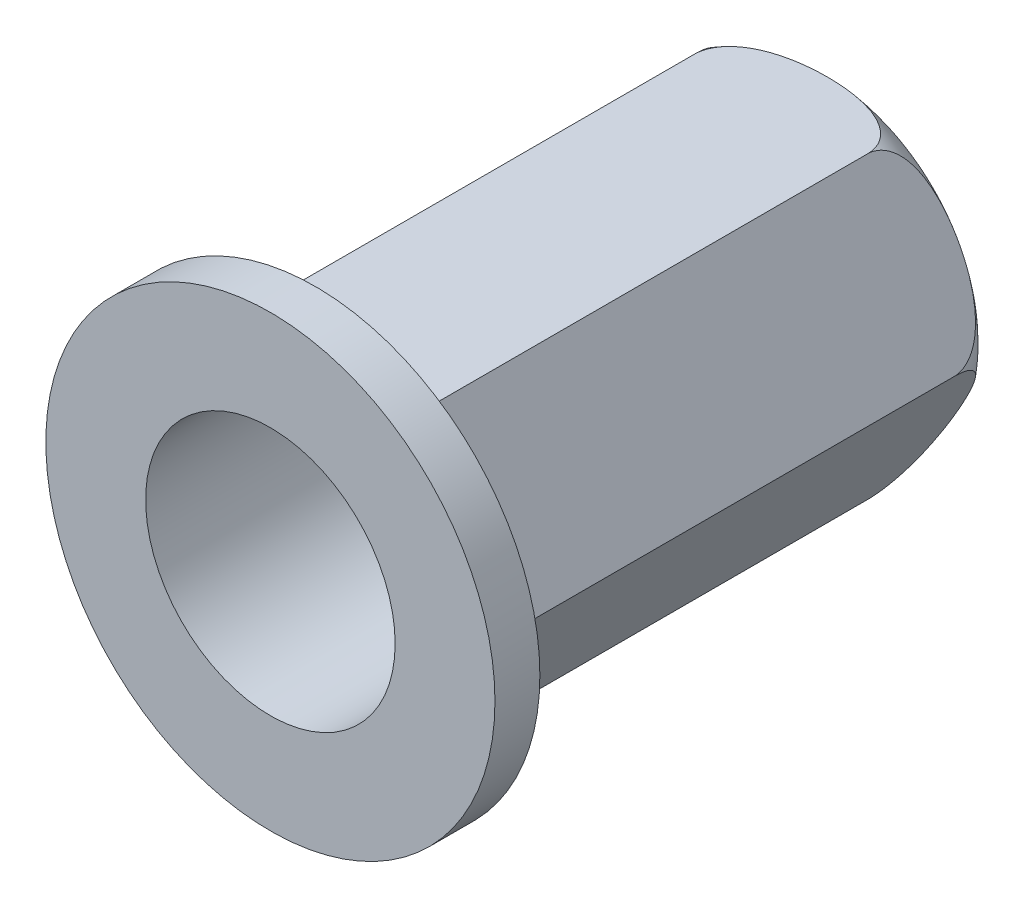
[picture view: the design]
ISO-10303-21;
HEADER;
FILE_DESCRIPTION(('STEP AP214'),'2;1');
FILE_NAME('part.step','',(''),(''),'','','');
FILE_SCHEMA(('AUTOMOTIVE_DESIGN { 1 0 10303 214 1 1 1 1 }'));
ENDSEC;
DATA;
#1=APPLICATION_CONTEXT('core data for automotive mechanical design processes');
#2=APPLICATION_PROTOCOL_DEFINITION('international standard','automotive_design',2000,#1);
#3=PRODUCT_CONTEXT('',#1,'mechanical');
#4=PRODUCT('Part','Part','',(#3));
#5=PRODUCT_RELATED_PRODUCT_CATEGORY('part','',(#4));
#6=PRODUCT_DEFINITION_FORMATION('','',#4);
#7=PRODUCT_DEFINITION_CONTEXT('part definition',#1,'design');
#8=PRODUCT_DEFINITION('design','',#6,#7);
#9=PRODUCT_DEFINITION_SHAPE('','',#8);
#10=(LENGTH_UNIT() NAMED_UNIT(*) SI_UNIT(.MILLI.,.METRE.));
#11=(NAMED_UNIT(*) PLANE_ANGLE_UNIT() SI_UNIT($,.RADIAN.));
#12=(NAMED_UNIT(*) SI_UNIT($,.STERADIAN.) SOLID_ANGLE_UNIT());
#13=UNCERTAINTY_MEASURE_WITH_UNIT(LENGTH_MEASURE(1.E-05),#10,'distance_accuracy_value','');
#14=(GEOMETRIC_REPRESENTATION_CONTEXT(3) GLOBAL_UNCERTAINTY_ASSIGNED_CONTEXT((#13)) GLOBAL_UNIT_ASSIGNED_CONTEXT((#10,
#11,#12)) REPRESENTATION_CONTEXT('',''));
#15=CARTESIAN_POINT('',(0.,0.,0.));
#16=DIRECTION('',(0.,0.,1.));
#17=DIRECTION('',(1.,0.,0.));
#18=AXIS2_PLACEMENT_3D('',#15,#16,#17);
#19=CARTESIAN_POINT('',(-3.46410161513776,6.,-22.8000000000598));
#20=DIRECTION('',(0.,-1.,0.));
#21=DIRECTION('',(1.,0.,0.));
#22=AXIS2_PLACEMENT_3D('',#19,#20,#21);
#23=PLANE('',#22);
#24=DIRECTION('',(0.,0.,1.));
#25=VECTOR('',#24,1.);
#26=CARTESIAN_POINT('',(-3.46410161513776,6.,-22.8000000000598));
#27=LINE('',#26,#25);
#28=CARTESIAN_POINT('',(-3.46410161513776,6.,-20.4666666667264));
#29=VERTEX_POINT('',#28);
#30=CARTESIAN_POINT('',(-3.46410161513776,6.,-2.70000000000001));
#31=VERTEX_POINT('',#30);
#32=EDGE_CURVE('E317',#29,#31,#27,.T.);
#33=ORIENTED_EDGE('',*,*,#32,.T.);
#34=DIRECTION('',(1.,0.,0.));
#35=VECTOR('',#34,1.);
#36=CARTESIAN_POINT('',(3.46410161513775,6.,-2.7));
#37=LINE('',#36,#35);
#38=CARTESIAN_POINT('',(3.46410161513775,6.,-2.70000000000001));
#39=VERTEX_POINT('',#38);
#40=EDGE_CURVE('E58',#31,#39,#37,.T.);
#41=ORIENTED_EDGE('',*,*,#40,.T.);
#42=DIRECTION('',(0.,0.,1.));
#43=VECTOR('',#42,1.);
#44=CARTESIAN_POINT('',(3.46410161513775,6.,-22.8000000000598));
#45=LINE('',#44,#43);
#46=CARTESIAN_POINT('',(3.46410161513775,6.00000000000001,-20.4666666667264));
#47=VERTEX_POINT('',#46);
#48=EDGE_CURVE('E126',#47,#39,#45,.T.);
#49=ORIENTED_EDGE('',*,*,#48,.F.);
#50=CARTESIAN_POINT('',(0.,6.,-22.3294747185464));
#51=CARTESIAN_POINT('',(0.154184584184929,6.,-22.3294717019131));
#52=CARTESIAN_POINT('',(0.308365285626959,6.,-22.3250239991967));
#53=CARTESIAN_POINT('',(0.616274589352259,6.,-22.3068259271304));
#54=CARTESIAN_POINT('',(0.770002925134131,6.,-22.2930708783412));
#55=CARTESIAN_POINT('',(1.07581899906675,6.,-22.2551025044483));
#56=CARTESIAN_POINT('',(1.22790980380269,6.,-22.2309145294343));
#57=CARTESIAN_POINT('',(1.52950724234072,6.,-22.1700841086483));
#58=CARTESIAN_POINT('',(1.67901642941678,6.,-22.1334548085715));
#59=CARTESIAN_POINT('',(1.94993108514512,6.,-22.0519178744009));
#60=CARTESIAN_POINT('',(2.07200596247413,6.,-22.0092722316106));
#61=CARTESIAN_POINT('',(2.31103064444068,6.,-21.9108273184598));
#62=CARTESIAN_POINT('',(2.42797468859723,6.,-21.8550136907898));
#63=CARTESIAN_POINT('',(2.65466542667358,6.,-21.7268580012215));
#64=CARTESIAN_POINT('',(2.76429762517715,6.,-21.6543087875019));
#65=CARTESIAN_POINT('',(2.96863454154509,6.,-21.4905393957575));
#66=CARTESIAN_POINT('',(3.06339501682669,6.,-21.3993920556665));
#67=CARTESIAN_POINT('',(3.19489580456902,6.,-21.2393492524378));
#68=CARTESIAN_POINT('',(3.23941987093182,6.,-21.1768508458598));
#69=CARTESIAN_POINT('',(3.31809199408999,6.,-21.0455705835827));
#70=CARTESIAN_POINT('',(3.35224628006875,6.,-20.9767925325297));
#71=CARTESIAN_POINT('',(3.40811056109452,6.,-20.8335865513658));
#72=CARTESIAN_POINT('',(3.42971034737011,6.,-20.7591148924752));
#73=CARTESIAN_POINT('',(3.45810849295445,6.,-20.6073950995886));
#74=CARTESIAN_POINT('',(3.46491843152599,6.,-20.5301491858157));
#75=CARTESIAN_POINT('',(3.46323187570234,6.,-20.3850698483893));
#76=CARTESIAN_POINT('',(3.45646076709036,6.,-20.317210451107));
#77=CARTESIAN_POINT('',(3.43148910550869,6.,-20.1836465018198));
#78=CARTESIAN_POINT('',(3.41328766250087,6.,-20.1179421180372));
#79=CARTESIAN_POINT('',(3.36687234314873,6.,-19.9908236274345));
#80=CARTESIAN_POINT('',(3.33874008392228,6.,-19.9293792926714));
#81=CARTESIAN_POINT('',(3.27399756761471,6.,-19.8111755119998));
#82=CARTESIAN_POINT('',(3.23738389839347,6.,-19.754417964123));
#83=CARTESIAN_POINT('',(3.13607560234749,6.,-19.6174288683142));
#84=CARTESIAN_POINT('',(3.06675759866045,6.,-19.5406125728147));
#85=CARTESIAN_POINT('',(2.91680568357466,6.,-19.3989627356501));
#86=CARTESIAN_POINT('',(2.83614367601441,6.,-19.3341599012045));
#87=CARTESIAN_POINT('',(2.61923773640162,6.,-19.1819547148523));
#88=CARTESIAN_POINT('',(2.47740993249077,6.,-19.1025706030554));
#89=CARTESIAN_POINT('',(2.18369947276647,6.,-18.9658033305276));
#90=CARTESIAN_POINT('',(2.03179656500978,6.,-18.9084661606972));
#91=CARTESIAN_POINT('',(1.73122572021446,6.,-18.813975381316));
#92=CARTESIAN_POINT('',(1.58284593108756,6.,-18.7758784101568));
#93=CARTESIAN_POINT('',(1.28333812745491,6.,-18.7122986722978));
#94=CARTESIAN_POINT('',(1.13220756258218,6.,-18.6868283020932));
#95=CARTESIAN_POINT('',(0.827947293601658,6.,-18.6463598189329));
#96=CARTESIAN_POINT('',(0.674811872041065,6.,-18.6314059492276));
#97=CARTESIAN_POINT('',(0.367996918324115,6.,-18.6108596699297));
#98=CARTESIAN_POINT('',(0.214317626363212,6.,-18.6052635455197));
#99=CARTESIAN_POINT('',(-0.112922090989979,6.,-18.6027641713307));
#100=CARTESIAN_POINT('',(-0.286492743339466,6.,-18.6070739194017));
#101=CARTESIAN_POINT('',(-0.633091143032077,6.,-18.627444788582));
#102=CARTESIAN_POINT('',(-0.806118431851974,6.,-18.6435140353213));
#103=CARTESIAN_POINT('',(-1.1498441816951,6.,-18.6891173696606));
#104=CARTESIAN_POINT('',(-1.32054853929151,6.,-18.7186057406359));
#105=CARTESIAN_POINT('',(-1.6581955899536,6.,-18.794096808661));
#106=CARTESIAN_POINT('',(-1.82514375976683,6.,-18.8400735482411));
#107=CARTESIAN_POINT('',(-2.07000778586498,6.,-18.9247765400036));
#108=CARTESIAN_POINT('',(-2.15064347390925,6.,-18.9556044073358));
#109=CARTESIAN_POINT('',(-2.30936935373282,6.,-19.0232052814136));
#110=CARTESIAN_POINT('',(-2.38745867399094,6.,-19.059980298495));
#111=CARTESIAN_POINT('',(-2.61579578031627,6.,-19.1800327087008));
#112=CARTESIAN_POINT('',(-2.76125765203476,6.,-19.2734038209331));
#113=CARTESIAN_POINT('',(-2.95841093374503,6.,-19.4366877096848));
#114=CARTESIAN_POINT('',(-3.02022108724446,6.,-19.4944504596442));
#115=CARTESIAN_POINT('',(-3.13514885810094,6.,-19.6182493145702));
#116=CARTESIAN_POINT('',(-3.18826346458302,6.,-19.6842882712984));
#117=CARTESIAN_POINT('',(-3.28337913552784,6.,-19.8251182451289));
#118=CARTESIAN_POINT('',(-3.32525323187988,6.,-19.8999965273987));
#119=CARTESIAN_POINT('',(-3.39377396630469,6.,-20.0564392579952));
#120=CARTESIAN_POINT('',(-3.42044481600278,6.,-20.1379928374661));
#121=CARTESIAN_POINT('',(-3.45387652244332,6.,-20.295254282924));
#122=CARTESIAN_POINT('',(-3.46258425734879,6.,-20.3705464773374));
#123=CARTESIAN_POINT('',(-3.46525164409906,6.,-20.5213846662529));
#124=CARTESIAN_POINT('',(-3.45921737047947,6.,-20.5969305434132));
#125=CARTESIAN_POINT('',(-3.43461422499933,6.,-20.7362646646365));
#126=CARTESIAN_POINT('',(-3.41768541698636,6.,-20.8003527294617));
#127=CARTESIAN_POINT('',(-3.37407256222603,6.,-20.9250874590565));
#128=CARTESIAN_POINT('',(-3.34738616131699,6.,-20.9857332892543));
#129=CARTESIAN_POINT('',(-3.27528134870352,6.,-21.1222767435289));
#130=CARTESIAN_POINT('',(-3.22658138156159,6.,-21.196439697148));
#131=CARTESIAN_POINT('',(-3.11781351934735,6.,-21.3358708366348));
#132=CARTESIAN_POINT('',(-3.05772509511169,6.,-21.401122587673));
#133=CARTESIAN_POINT('',(-2.90009049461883,6.,-21.5503465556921));
#134=CARTESIAN_POINT('',(-2.79791245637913,6.,-21.629395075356));
#135=CARTESIAN_POINT('',(-2.58266696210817,6.,-21.7708478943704));
#136=CARTESIAN_POINT('',(-2.46957433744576,6.,-21.8332124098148));
#137=CARTESIAN_POINT('',(-2.25226314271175,6.,-21.9364464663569));
#138=CARTESIAN_POINT('',(-2.14885789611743,6.,-21.9790700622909));
#139=CARTESIAN_POINT('',(-1.93871953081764,6.,-22.0552719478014));
#140=CARTESIAN_POINT('',(-1.83198377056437,6.,-22.0888428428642));
#141=CARTESIAN_POINT('',(-1.6163074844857,6.,-22.148268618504));
#142=CARTESIAN_POINT('',(-1.50736488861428,6.,-22.1741158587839));
#143=CARTESIAN_POINT('',(-1.28816765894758,6.,-22.2191255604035));
#144=CARTESIAN_POINT('',(-1.1779134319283,6.,-22.2382900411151));
#145=CARTESIAN_POINT('',(-0.890703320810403,6.,-22.2804820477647));
#146=CARTESIAN_POINT('',(-0.713086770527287,6.,-22.2990251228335));
#147=CARTESIAN_POINT('',(-0.356978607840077,6.,-22.323525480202));
#148=CARTESIAN_POINT('',(-0.17848670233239,6.,-22.3294782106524));
#149=CARTESIAN_POINT('',(0.,6.,-22.3294747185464));
#150=B_SPLINE_CURVE_WITH_KNOTS('',3,(#50,#51,#52,#53,#54,#55,#56,#57,#58,#59,#60,#61,#62,#63,
#64,#65,#66,#67,#68,#69,#70,#71,#72,#73,#74,#75,#76,#77,#78,#79,#80,#81,#82,#83,#84,#85,#86,#87,
#88,#89,#90,#91,#92,#93,#94,#95,#96,#97,#98,#99,#100,#101,#102,#103,#104,#105,#106,#107,#108,
#109,#110,#111,#112,#113,#114,#115,#116,#117,#118,#119,#120,#121,#122,#123,#124,#125,#126,#127,
#128,#129,#130,#131,#132,#133,#134,#135,#136,#137,#138,#139,#140,#141,#142,#143,#144,#145,#146,
#147,#148,#149),.UNSPECIFIED.,.T.,.F.,(4,2,2,2,2,2,2,2,2,2,2,2,2,2,2,2,2,2,2,2,2,2,2,2,2,2,2,2,
2,2,2,2,2,2,2,2,2,2,2,2,2,2,2,2,2,2,2,2,2,4),(0.,0.462479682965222,0.925192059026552,
1.38678640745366,1.84789453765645,2.23523118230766,2.62299211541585,3.01583805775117,
3.40717400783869,3.63659218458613,3.86587227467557,4.09713581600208,4.32821823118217,
4.53179583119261,4.73538928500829,4.93734702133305,5.13938614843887,5.44802668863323,
5.75744557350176,6.24229747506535,6.72815538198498,7.18705566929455,7.64640560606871,
8.10767666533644,8.56876456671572,9.08926420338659,9.61012383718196,10.1292221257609,
10.6475067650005,10.9062553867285,11.1650916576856,11.6791912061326,11.9323360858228,
12.1855684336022,12.4415511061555,12.6971249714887,12.9231229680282,13.1490278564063,
13.3470334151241,13.5450867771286,13.8097838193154,14.074962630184,14.4603581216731,
14.8466645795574,15.1817185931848,15.517045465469,15.8527029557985,16.1882589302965,
16.7234398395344,17.2588142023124),.UNSPECIFIED.);
#151=EDGE_CURVE('E114',#29,#47,#150,.T.);
#152=ORIENTED_EDGE('',*,*,#151,.F.);
#153=EDGE_LOOP('',(#33,#41,#49,#152));
#154=FACE_BOUND('',#153,.T.);
#155=ADVANCED_FACE('F35',(#154),#23,.F.);
#156=CARTESIAN_POINT('',(3.46410161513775,6.,-22.8000000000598));
#157=DIRECTION('',(-0.866025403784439,-0.5,0.));
#158=DIRECTION('',(0.5,-0.866025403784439,0.));
#159=AXIS2_PLACEMENT_3D('',#156,#157,#158);
#160=PLANE('',#159);
#161=ORIENTED_EDGE('',*,*,#48,.T.);
#162=DIRECTION('',(0.5,-0.866025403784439,0.));
#163=VECTOR('',#162,1.);
#164=CARTESIAN_POINT('',(6.92820323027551,0.,-2.7));
#165=LINE('',#164,#163);
#166=CARTESIAN_POINT('',(6.92820323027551,0.,-2.70000000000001));
#167=VERTEX_POINT('',#166);
#168=EDGE_CURVE('E50',#39,#167,#165,.T.);
#169=ORIENTED_EDGE('',*,*,#168,.T.);
#170=DIRECTION('',(0.,0.,1.));
#171=VECTOR('',#170,1.);
#172=CARTESIAN_POINT('',(6.92820323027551,0.,-22.8000000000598));
#173=LINE('',#172,#171);
#174=CARTESIAN_POINT('',(6.92820323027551,0.,-20.4666666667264));
#175=VERTEX_POINT('',#174);
#176=EDGE_CURVE('E119',#175,#167,#173,.T.);
#177=ORIENTED_EDGE('',*,*,#176,.F.);
#178=CARTESIAN_POINT('',(3.46410162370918,5.99999998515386,-20.4664666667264));
#179=CARTESIAN_POINT('',(3.46409613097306,6.00000949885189,-20.5007988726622));
#180=CARTESIAN_POINT('',(3.46485408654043,5.99869668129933,-20.5351131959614));
#181=CARTESIAN_POINT('',(3.46786667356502,5.99347872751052,-20.6034580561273));
#182=CARTESIAN_POINT('',(3.47012041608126,5.9895751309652,-20.6374887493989));
#183=CARTESIAN_POINT('',(3.47903492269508,5.97413475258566,-20.7383191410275));
#184=CARTESIAN_POINT('',(3.48784998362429,5.95886661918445,-20.8043983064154));
#185=CARTESIAN_POINT('',(3.51062418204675,5.91942055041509,-20.9326667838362));
#186=CARTESIAN_POINT('',(3.52457273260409,5.89526095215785,-20.9948637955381));
#187=CARTESIAN_POINT('',(3.55684476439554,5.83936415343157,-21.1146179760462));
#188=CARTESIAN_POINT('',(3.57517617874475,5.80761321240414,-21.1721664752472));
#189=CARTESIAN_POINT('',(3.62554504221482,5.72037178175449,-21.3097398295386));
#190=CARTESIAN_POINT('',(3.65983314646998,5.66098304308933,-21.3864692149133));
#191=CARTESIAN_POINT('',(3.73406030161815,5.5324178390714,-21.5280409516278));
#192=CARTESIAN_POINT('',(3.77401200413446,5.46321946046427,-21.5928559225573));
#193=CARTESIAN_POINT('',(3.88136050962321,5.27728639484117,-21.7449917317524));
#194=CARTESIAN_POINT('',(3.95153570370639,5.1557393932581,-21.8244109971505));
#195=CARTESIAN_POINT('',(4.0969239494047,4.90391956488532,-21.9614331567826));
#196=CARTESIAN_POINT('',(4.1721466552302,4.77363001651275,-22.0189927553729));
#197=CARTESIAN_POINT('',(4.32084175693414,4.5160825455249,-22.1139087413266));
#198=CARTESIAN_POINT('',(4.39416238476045,4.38908749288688,-22.1522437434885));
#199=CARTESIAN_POINT('',(4.5421909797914,4.13269444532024,-22.2164376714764));
#200=CARTESIAN_POINT('',(4.61690023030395,4.00329422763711,-22.2422843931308));
#201=CARTESIAN_POINT('',(4.76737474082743,3.74266473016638,-22.2836382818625));
#202=CARTESIAN_POINT('',(4.8431433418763,3.61142966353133,-22.2990954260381));
#203=CARTESIAN_POINT('',(4.99496902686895,3.34845986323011,-22.3207691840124));
#204=CARTESIAN_POINT('',(5.0710259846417,3.21672534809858,-22.3269894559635));
#205=CARTESIAN_POINT('',(5.23315937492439,2.93590207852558,-22.3309963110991));
#206=CARTESIAN_POINT('',(5.31924369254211,2.78679966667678,-22.3275718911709));
#207=CARTESIAN_POINT('',(5.49117705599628,2.48900234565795,-22.309246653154));
#208=CARTESIAN_POINT('',(5.57702590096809,2.34030778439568,-22.2943379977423));
#209=CARTESIAN_POINT('',(5.74735291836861,2.04529273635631,-22.25154782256));
#210=CARTESIAN_POINT('',(5.83183641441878,1.89896302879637,-22.2237535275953));
#211=CARTESIAN_POINT('',(5.99906894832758,1.60930778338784,-22.1523915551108));
#212=CARTESIAN_POINT('',(6.08182056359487,1.46597778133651,-22.1088493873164));
#213=CARTESIAN_POINT('',(6.21706293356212,1.23173112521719,-22.01958472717));
#214=CARTESIAN_POINT('',(6.27046157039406,1.13924197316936,-21.9794075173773));
#215=CARTESIAN_POINT('',(6.37506563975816,0.958062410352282,-21.8884695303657));
#216=CARTESIAN_POINT('',(6.42626897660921,0.869375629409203,-21.8376989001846));
#217=CARTESIAN_POINT('',(6.52561921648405,0.697295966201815,-21.7233224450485));
#218=CARTESIAN_POINT('',(6.57373557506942,0.613955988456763,-21.6596085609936));
#219=CARTESIAN_POINT('',(6.66441515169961,0.456894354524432,-21.5178650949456));
#220=CARTESIAN_POINT('',(6.70698917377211,0.383153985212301,-21.4398641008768));
#221=CARTESIAN_POINT('',(6.77172738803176,0.271024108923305,-21.2954372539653));
#222=CARTESIAN_POINT('',(6.79611247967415,0.228787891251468,-21.2330087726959));
#223=CARTESIAN_POINT('',(6.83970596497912,0.153281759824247,-21.1012335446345));
#224=CARTESIAN_POINT('',(6.85891864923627,0.120004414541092,-21.0318925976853));
#225=CARTESIAN_POINT('',(6.8887938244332,0.0682590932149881,-20.8969339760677));
#226=CARTESIAN_POINT('',(6.90024702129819,0.0484215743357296,-20.8320199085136));
#227=CARTESIAN_POINT('',(6.91752136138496,0.0185015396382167,-20.6993345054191));
#228=CARTESIAN_POINT('',(6.92335508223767,0.00839723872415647,-20.6315699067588));
#229=CARTESIAN_POINT('',(6.92754146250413,0.00114621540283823,-20.5311268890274));
#230=CARTESIAN_POINT('',(6.92821688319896,-2.36475570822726E-05,-20.4987901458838));
#231=CARTESIAN_POINT('',(6.92820322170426,1.48458359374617E-08,-20.4664666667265));
#232=B_SPLINE_CURVE_WITH_KNOTS('',3,(#178,#179,#180,#181,#182,#183,#184,#185,#186,#187,#188,
#189,#190,#191,#192,#193,#194,#195,#196,#197,#198,#199,#200,#201,#202,#203,#204,#205,#206,#207,
#208,#209,#210,#211,#212,#213,#214,#215,#216,#217,#218,#219,#220,#221,#222,#223,#224,#225,#226,
#227,#228,#229,#230,#231),.UNSPECIFIED.,.F.,.F.,(4,2,2,2,2,2,2,2,2,2,2,2,2,2,2,2,2,2,2,2,2,2,2,
2,2,2,4),(0.,0.102928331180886,0.20579554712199,0.409928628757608,0.613643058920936,
0.817729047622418,1.12470488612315,1.43237759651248,1.91344083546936,2.39545196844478,
2.8494900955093,3.3039710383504,3.76062479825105,4.21709765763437,4.73334323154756,
5.24994142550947,5.76309263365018,6.27541629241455,6.61728597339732,6.95947505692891,
7.30464793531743,7.64913753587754,7.88599898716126,8.1226633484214,8.32830181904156,
8.53347894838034,8.63046058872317),.UNSPECIFIED.);
#233=EDGE_CURVE('E108',#47,#175,#232,.T.);
#234=ORIENTED_EDGE('',*,*,#233,.F.);
#235=EDGE_LOOP('',(#161,#169,#177,#234));
#236=FACE_BOUND('',#235,.T.);
#237=ADVANCED_FACE('F125',(#236),#160,.F.);
#238=CARTESIAN_POINT('',(6.92820323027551,0.,-22.8000000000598));
#239=DIRECTION('',(-0.866025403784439,0.5,0.));
#240=DIRECTION('',(-0.5,-0.866025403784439,0.));
#241=AXIS2_PLACEMENT_3D('',#238,#239,#240);
#242=PLANE('',#241);
#243=ORIENTED_EDGE('',*,*,#176,.T.);
#244=DIRECTION('',(-0.5,-0.866025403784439,0.));
#245=VECTOR('',#244,1.);
#246=CARTESIAN_POINT('',(3.46410161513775,-6.00000000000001,-2.7));
#247=LINE('',#246,#245);
#248=CARTESIAN_POINT('',(3.46410161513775,-6.,-2.70000000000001));
#249=VERTEX_POINT('',#248);
#250=EDGE_CURVE('E161',#167,#249,#247,.T.);
#251=ORIENTED_EDGE('',*,*,#250,.T.);
#252=DIRECTION('',(0.,0.,1.));
#253=VECTOR('',#252,1.);
#254=CARTESIAN_POINT('',(3.46410161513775,-6.,-22.8000000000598));
#255=LINE('',#254,#253);
#256=CARTESIAN_POINT('',(3.46410161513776,-6.,-20.4666666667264));
#257=VERTEX_POINT('',#256);
#258=EDGE_CURVE('E122',#257,#249,#255,.T.);
#259=ORIENTED_EDGE('',*,*,#258,.F.);
#260=CARTESIAN_POINT('',(6.92820322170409,-1.48461442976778E-08,-20.4664666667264));
#261=CARTESIAN_POINT('',(6.92820871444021,9.49885189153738E-06,-20.5007988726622));
#262=CARTESIAN_POINT('',(6.92745075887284,-0.00130331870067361,-20.5351131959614));
#263=CARTESIAN_POINT('',(6.92443817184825,-0.00652127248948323,-20.6034580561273));
#264=CARTESIAN_POINT('',(6.922184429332,-0.0104248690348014,-20.6374887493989));
#265=CARTESIAN_POINT('',(6.91326992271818,-0.0258652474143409,-20.7383191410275));
#266=CARTESIAN_POINT('',(6.90445486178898,-0.0411333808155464,-20.8043983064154));
#267=CARTESIAN_POINT('',(6.88168066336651,-0.0805794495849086,-20.9326667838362));
#268=CARTESIAN_POINT('',(6.86773211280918,-0.104739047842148,-20.9948637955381));
#269=CARTESIAN_POINT('',(6.83546008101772,-0.16063584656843,-21.1146179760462));
#270=CARTESIAN_POINT('',(6.81712866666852,-0.192386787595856,-21.1721664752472));
#271=CARTESIAN_POINT('',(6.76675980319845,-0.279628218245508,-21.3097398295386));
#272=CARTESIAN_POINT('',(6.73247169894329,-0.339016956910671,-21.3864692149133));
#273=CARTESIAN_POINT('',(6.65824454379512,-0.467582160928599,-21.5280409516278));
#274=CARTESIAN_POINT('',(6.61829284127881,-0.536780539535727,-21.5928559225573));
#275=CARTESIAN_POINT('',(6.51094433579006,-0.722713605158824,-21.7449917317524));
#276=CARTESIAN_POINT('',(6.44076914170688,-0.844260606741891,-21.8244109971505));
#277=CARTESIAN_POINT('',(6.29538089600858,-1.09608043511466,-21.9614331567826));
#278=CARTESIAN_POINT('',(6.22015819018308,-1.22636998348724,-22.0189927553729));
#279=CARTESIAN_POINT('',(6.07146308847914,-1.48391745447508,-22.1139087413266));
#280=CARTESIAN_POINT('',(5.99814246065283,-1.6109125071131,-22.1522437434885));
#281=CARTESIAN_POINT('',(5.85011386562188,-1.86730555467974,-22.2164376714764));
#282=CARTESIAN_POINT('',(5.77540461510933,-1.99670577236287,-22.2422843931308));
#283=CARTESIAN_POINT('',(5.62493010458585,-2.25733526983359,-22.2836382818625));
#284=CARTESIAN_POINT('',(5.54916150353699,-2.38857033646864,-22.2990954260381));
#285=CARTESIAN_POINT('',(5.39733581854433,-2.65154013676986,-22.3207691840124));
#286=CARTESIAN_POINT('',(5.32127886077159,-2.78327465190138,-22.3269894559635));
#287=CARTESIAN_POINT('',(5.1591454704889,-3.06409792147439,-22.3309963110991));
#288=CARTESIAN_POINT('',(5.07306115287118,-3.21320033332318,-22.3275718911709));
#289=CARTESIAN_POINT('',(4.90112778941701,-3.51099765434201,-22.309246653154));
#290=CARTESIAN_POINT('',(4.8152789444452,-3.65969221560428,-22.2943379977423));
#291=CARTESIAN_POINT('',(4.64495192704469,-3.95470726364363,-22.25154782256));
#292=CARTESIAN_POINT('',(4.56046843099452,-4.10103697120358,-22.2237535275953));
#293=CARTESIAN_POINT('',(4.39323589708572,-4.39069221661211,-22.1523915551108));
#294=CARTESIAN_POINT('',(4.31048428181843,-4.53402221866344,-22.1088493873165));
#295=CARTESIAN_POINT('',(4.17524191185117,-4.76826887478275,-22.01958472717));
#296=CARTESIAN_POINT('',(4.12184327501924,-4.86075802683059,-21.9794075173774));
#297=CARTESIAN_POINT('',(4.01723920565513,-5.04193758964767,-21.8884695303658));
#298=CARTESIAN_POINT('',(3.96603586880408,-5.13062437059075,-21.8376989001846));
#299=CARTESIAN_POINT('',(3.86668562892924,-5.30270403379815,-21.7233224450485));
#300=CARTESIAN_POINT('',(3.81856927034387,-5.3860440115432,-21.6596085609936));
#301=CARTESIAN_POINT('',(3.72788969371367,-5.54310564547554,-21.5178650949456));
#302=CARTESIAN_POINT('',(3.68531567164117,-5.61684601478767,-21.4398641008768));
#303=CARTESIAN_POINT('',(3.62057745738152,-5.72897589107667,-21.2954372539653));
#304=CARTESIAN_POINT('',(3.59619236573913,-5.77121210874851,-21.2330087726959));
#305=CARTESIAN_POINT('',(3.55259888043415,-5.84671824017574,-21.1012335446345));
#306=CARTESIAN_POINT('',(3.53338619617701,-5.87999558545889,-21.0318925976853));
#307=CARTESIAN_POINT('',(3.50351102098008,-5.931740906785,-20.8969339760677));
#308=CARTESIAN_POINT('',(3.49205782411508,-5.95157842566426,-20.8320199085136));
#309=CARTESIAN_POINT('',(3.47478348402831,-5.98149846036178,-20.6993345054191));
#310=CARTESIAN_POINT('',(3.4689497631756,-5.99160276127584,-20.6315699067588));
#311=CARTESIAN_POINT('',(3.46476338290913,-5.99885378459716,-20.5311268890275));
#312=CARTESIAN_POINT('',(3.46408796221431,-6.00002364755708,-20.4987901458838));
#313=CARTESIAN_POINT('',(3.46410162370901,-5.99999998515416,-20.4664666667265));
#314=B_SPLINE_CURVE_WITH_KNOTS('',3,(#260,#261,#262,#263,#264,#265,#266,#267,#268,#269,#270,
#271,#272,#273,#274,#275,#276,#277,#278,#279,#280,#281,#282,#283,#284,#285,#286,#287,#288,#289,
#290,#291,#292,#293,#294,#295,#296,#297,#298,#299,#300,#301,#302,#303,#304,#305,#306,#307,#308,
#309,#310,#311,#312,#313),.UNSPECIFIED.,.F.,.F.,(4,2,2,2,2,2,2,2,2,2,2,2,2,2,2,2,2,2,2,2,2,2,2,
2,2,2,4),(0.,0.102928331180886,0.20579554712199,0.409928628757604,0.613643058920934,
0.817729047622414,1.12470488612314,1.43237759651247,1.91344083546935,2.39545196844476,
2.84949009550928,3.30397103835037,3.76062479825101,4.21709765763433,4.73334323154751,
5.24994142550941,5.76309263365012,6.27541629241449,6.61728597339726,6.95947505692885,
7.30464793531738,7.64913753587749,7.88599898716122,8.12266334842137,8.32830181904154,
8.53347894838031,8.63046058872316),.UNSPECIFIED.);
#315=EDGE_CURVE('E111',#175,#257,#314,.T.);
#316=ORIENTED_EDGE('',*,*,#315,.F.);
#317=EDGE_LOOP('',(#243,#251,#259,#316));
#318=FACE_BOUND('',#317,.T.);
#319=ADVANCED_FACE('F118',(#318),#242,.F.);
#320=CARTESIAN_POINT('',(3.46410161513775,-6.,-22.8000000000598));
#321=DIRECTION('',(0.,1.,0.));
#322=DIRECTION('',(-1.,0.,0.));
#323=AXIS2_PLACEMENT_3D('',#320,#321,#322);
#324=PLANE('',#323);
#325=ORIENTED_EDGE('',*,*,#258,.T.);
#326=DIRECTION('',(-1.,0.,0.));
#327=VECTOR('',#326,1.);
#328=CARTESIAN_POINT('',(-3.46410161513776,-6.,-2.7));
#329=LINE('',#328,#327);
#330=CARTESIAN_POINT('',(-3.46410161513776,-6.,-2.70000000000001));
#331=VERTEX_POINT('',#330);
#332=EDGE_CURVE('E137',#249,#331,#329,.T.);
#333=ORIENTED_EDGE('',*,*,#332,.T.);
#334=DIRECTION('',(0.,0.,1.));
#335=VECTOR('',#334,1.);
#336=CARTESIAN_POINT('',(-3.46410161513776,-6.,-22.8000000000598));
#337=LINE('',#336,#335);
#338=CARTESIAN_POINT('',(-3.46410161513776,-6.,-20.4666666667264));
#339=VERTEX_POINT('',#338);
#340=EDGE_CURVE('E130',#339,#331,#337,.T.);
#341=ORIENTED_EDGE('',*,*,#340,.F.);
#342=CARTESIAN_POINT('',(0.,-6.,-22.3294747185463));
#343=CARTESIAN_POINT('',(-0.154184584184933,-6.,-22.3294717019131));
#344=CARTESIAN_POINT('',(-0.308365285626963,-6.,-22.3250239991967));
#345=CARTESIAN_POINT('',(-0.616274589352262,-6.,-22.3068259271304));
#346=CARTESIAN_POINT('',(-0.770002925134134,-6.,-22.2930708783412));
#347=CARTESIAN_POINT('',(-1.07581899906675,-6.,-22.2551025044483));
#348=CARTESIAN_POINT('',(-1.22790980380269,-6.,-22.2309145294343));
#349=CARTESIAN_POINT('',(-1.52950724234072,-6.,-22.1700841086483));
#350=CARTESIAN_POINT('',(-1.67901642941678,-6.,-22.1334548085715));
#351=CARTESIAN_POINT('',(-1.94993108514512,-6.,-22.0519178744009));
#352=CARTESIAN_POINT('',(-2.07200596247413,-6.,-22.0092722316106));
#353=CARTESIAN_POINT('',(-2.31103064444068,-6.,-21.9108273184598));
#354=CARTESIAN_POINT('',(-2.42797468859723,-6.,-21.8550136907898));
#355=CARTESIAN_POINT('',(-2.65466542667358,-6.,-21.7268580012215));
#356=CARTESIAN_POINT('',(-2.76429762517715,-6.,-21.6543087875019));
#357=CARTESIAN_POINT('',(-2.96863454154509,-6.,-21.4905393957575));
#358=CARTESIAN_POINT('',(-3.0633950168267,-6.,-21.3993920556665));
#359=CARTESIAN_POINT('',(-3.19489580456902,-6.,-21.2393492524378));
#360=CARTESIAN_POINT('',(-3.23941987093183,-6.,-21.1768508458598));
#361=CARTESIAN_POINT('',(-3.31809199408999,-6.,-21.0455705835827));
#362=CARTESIAN_POINT('',(-3.35224628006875,-6.,-20.9767925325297));
#363=CARTESIAN_POINT('',(-3.40811056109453,-6.,-20.8335865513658));
#364=CARTESIAN_POINT('',(-3.42971034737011,-6.,-20.7591148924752));
#365=CARTESIAN_POINT('',(-3.45810849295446,-6.,-20.6073950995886));
#366=CARTESIAN_POINT('',(-3.46491843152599,-6.,-20.5301491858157));
#367=CARTESIAN_POINT('',(-3.46323187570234,-6.,-20.3850698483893));
#368=CARTESIAN_POINT('',(-3.45646076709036,-6.,-20.317210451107));
#369=CARTESIAN_POINT('',(-3.43148910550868,-6.,-20.1836465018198));
#370=CARTESIAN_POINT('',(-3.41328766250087,-6.,-20.1179421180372));
#371=CARTESIAN_POINT('',(-3.36687234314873,-6.,-19.9908236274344));
#372=CARTESIAN_POINT('',(-3.33874008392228,-6.,-19.9293792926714));
#373=CARTESIAN_POINT('',(-3.27399756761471,-6.,-19.8111755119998));
#374=CARTESIAN_POINT('',(-3.23738389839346,-6.,-19.754417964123));
#375=CARTESIAN_POINT('',(-3.13607560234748,-6.,-19.6174288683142));
#376=CARTESIAN_POINT('',(-3.06675759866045,-6.,-19.5406125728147));
#377=CARTESIAN_POINT('',(-2.91680568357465,-6.,-19.3989627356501));
#378=CARTESIAN_POINT('',(-2.8361436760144,-6.,-19.3341599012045));
#379=CARTESIAN_POINT('',(-2.61923773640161,-6.,-19.1819547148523));
#380=CARTESIAN_POINT('',(-2.47740993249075,-6.,-19.1025706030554));
#381=CARTESIAN_POINT('',(-2.18369947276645,-6.,-18.9658033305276));
#382=CARTESIAN_POINT('',(-2.03179656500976,-6.,-18.9084661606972));
#383=CARTESIAN_POINT('',(-1.73122572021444,-6.,-18.8139753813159));
#384=CARTESIAN_POINT('',(-1.58284593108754,-6.,-18.7758784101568));
#385=CARTESIAN_POINT('',(-1.28333812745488,-6.,-18.7122986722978));
#386=CARTESIAN_POINT('',(-1.13220756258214,-6.,-18.6868283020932));
#387=CARTESIAN_POINT('',(-0.827947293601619,-6.,-18.6463598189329));
#388=CARTESIAN_POINT('',(-0.674811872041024,-6.,-18.6314059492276));
#389=CARTESIAN_POINT('',(-0.36799691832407,-6.,-18.6108596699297));
#390=CARTESIAN_POINT('',(-0.214317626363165,-6.,-18.6052635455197));
#391=CARTESIAN_POINT('',(0.112922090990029,-6.,-18.6027641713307));
#392=CARTESIAN_POINT('',(0.286492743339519,-6.,-18.6070739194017));
#393=CARTESIAN_POINT('',(0.633091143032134,-6.,-18.627444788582));
#394=CARTESIAN_POINT('',(0.806118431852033,-6.,-18.6435140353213));
#395=CARTESIAN_POINT('',(1.14984418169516,-6.,-18.6891173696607));
#396=CARTESIAN_POINT('',(1.32054853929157,-6.,-18.7186057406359));
#397=CARTESIAN_POINT('',(1.65819558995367,-6.,-18.794096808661));
#398=CARTESIAN_POINT('',(1.8251437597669,-6.,-18.8400735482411));
#399=CARTESIAN_POINT('',(2.07000778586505,-6.,-18.9247765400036));
#400=CARTESIAN_POINT('',(2.15064347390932,-6.,-18.9556044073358));
#401=CARTESIAN_POINT('',(2.30936935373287,-6.,-19.0232052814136));
#402=CARTESIAN_POINT('',(2.38745867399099,-6.,-19.059980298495));
#403=CARTESIAN_POINT('',(2.61579578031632,-6.,-19.1800327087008));
#404=CARTESIAN_POINT('',(2.7612576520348,-6.,-19.2734038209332));
#405=CARTESIAN_POINT('',(2.95841093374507,-6.,-19.4366877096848));
#406=CARTESIAN_POINT('',(3.02022108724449,-6.,-19.4944504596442));
#407=CARTESIAN_POINT('',(3.13514885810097,-6.,-19.6182493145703));
#408=CARTESIAN_POINT('',(3.18826346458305,-6.,-19.6842882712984));
#409=CARTESIAN_POINT('',(3.28337913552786,-6.,-19.8251182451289));
#410=CARTESIAN_POINT('',(3.3252532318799,-6.,-19.8999965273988));
#411=CARTESIAN_POINT('',(3.3937739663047,-6.,-20.0564392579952));
#412=CARTESIAN_POINT('',(3.42044481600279,-6.,-20.1379928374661));
#413=CARTESIAN_POINT('',(3.45387652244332,-6.,-20.295254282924));
#414=CARTESIAN_POINT('',(3.46258425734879,-6.,-20.3705464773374));
#415=CARTESIAN_POINT('',(3.46525164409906,-6.,-20.521384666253));
#416=CARTESIAN_POINT('',(3.45921737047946,-6.,-20.5969305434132));
#417=CARTESIAN_POINT('',(3.43461422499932,-6.,-20.7362646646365));
#418=CARTESIAN_POINT('',(3.41768541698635,-6.,-20.8003527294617));
#419=CARTESIAN_POINT('',(3.37407256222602,-6.,-20.9250874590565));
#420=CARTESIAN_POINT('',(3.34738616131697,-6.,-20.9857332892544));
#421=CARTESIAN_POINT('',(3.2752813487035,-6.,-21.1222767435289));
#422=CARTESIAN_POINT('',(3.22658138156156,-6.,-21.196439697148));
#423=CARTESIAN_POINT('',(3.11781351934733,-6.,-21.3358708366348));
#424=CARTESIAN_POINT('',(3.05772509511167,-6.,-21.4011225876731));
#425=CARTESIAN_POINT('',(2.9000904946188,-6.,-21.5503465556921));
#426=CARTESIAN_POINT('',(2.7979124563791,-6.,-21.629395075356));
#427=CARTESIAN_POINT('',(2.58266696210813,-6.,-21.7708478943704));
#428=CARTESIAN_POINT('',(2.46957433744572,-6.,-21.8332124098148));
#429=CARTESIAN_POINT('',(2.2522631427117,-6.,-21.9364464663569));
#430=CARTESIAN_POINT('',(2.14885789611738,-6.,-21.9790700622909));
#431=CARTESIAN_POINT('',(1.93871953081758,-6.,-22.0552719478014));
#432=CARTESIAN_POINT('',(1.83198377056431,-6.,-22.0888428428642));
#433=CARTESIAN_POINT('',(1.61630748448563,-6.,-22.148268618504));
#434=CARTESIAN_POINT('',(1.5073648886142,-6.,-22.1741158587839));
#435=CARTESIAN_POINT('',(1.28816765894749,-6.,-22.2191255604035));
#436=CARTESIAN_POINT('',(1.17791343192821,-6.,-22.2382900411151));
#437=CARTESIAN_POINT('',(0.890703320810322,-6.,-22.2804820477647));
#438=CARTESIAN_POINT('',(0.713086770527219,-6.,-22.2990251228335));
#439=CARTESIAN_POINT('',(0.35697860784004,-6.,-22.323525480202));
#440=CARTESIAN_POINT('',(0.178486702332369,-6.,-22.3294782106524));
#441=CARTESIAN_POINT('',(0.,-6.,-22.3294747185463));
#442=B_SPLINE_CURVE_WITH_KNOTS('',3,(#342,#343,#344,#345,#346,#347,#348,#349,#350,#351,#352,
#353,#354,#355,#356,#357,#358,#359,#360,#361,#362,#363,#364,#365,#366,#367,#368,#369,#370,#371,
#372,#373,#374,#375,#376,#377,#378,#379,#380,#381,#382,#383,#384,#385,#386,#387,#388,#389,#390,
#391,#392,#393,#394,#395,#396,#397,#398,#399,#400,#401,#402,#403,#404,#405,#406,#407,#408,#409,
#410,#411,#412,#413,#414,#415,#416,#417,#418,#419,#420,#421,#422,#423,#424,#425,#426,#427,#428,
#429,#430,#431,#432,#433,#434,#435,#436,#437,#438,#439,#440,#441),.UNSPECIFIED.,.T.,.F.,(4,2,2,
2,2,2,2,2,2,2,2,2,2,2,2,2,2,2,2,2,2,2,2,2,2,2,2,2,2,2,2,2,2,2,2,2,2,2,2,2,2,2,2,2,2,2,2,2,2,4),
(0.,0.46247968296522,0.92519205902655,1.38678640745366,1.84789453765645,2.23523118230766,
2.62299211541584,3.01583805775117,3.40717400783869,3.63659218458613,3.86587227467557,
4.09713581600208,4.32821823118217,4.5317958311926,4.73538928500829,4.93734702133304,
5.13938614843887,5.44802668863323,5.75744557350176,6.24229747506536,6.728155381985,
7.18705566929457,7.64640560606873,8.10767666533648,8.56876456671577,9.08926420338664,
9.61012383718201,10.129222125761,10.6475067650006,10.9062553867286,11.1650916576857,
11.6791912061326,11.9323360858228,12.1855684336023,12.4415511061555,12.6971249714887,
12.9231229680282,13.1490278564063,13.3470334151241,13.5450867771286,13.8097838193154,
14.0749626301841,14.4603581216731,14.8466645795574,15.1817185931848,15.5170454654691,
15.8527029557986,16.1882589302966,16.7234398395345,17.2588142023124),.UNSPECIFIED.);
#443=EDGE_CURVE('E123',#257,#339,#442,.T.);
#444=ORIENTED_EDGE('',*,*,#443,.F.);
#445=EDGE_LOOP('',(#325,#333,#341,#444));
#446=FACE_BOUND('',#445,.T.);
#447=ADVANCED_FACE('F306',(#446),#324,.F.);
#448=CARTESIAN_POINT('',(-3.46410161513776,-6.,-22.8000000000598));
#449=DIRECTION('',(0.866025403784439,0.5,0.));
#450=DIRECTION('',(-0.5,0.866025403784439,0.));
#451=AXIS2_PLACEMENT_3D('',#448,#449,#450);
#452=PLANE('',#451);
#453=ORIENTED_EDGE('',*,*,#340,.T.);
#454=DIRECTION('',(-0.5,0.866025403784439,0.));
#455=VECTOR('',#454,1.);
#456=CARTESIAN_POINT('',(-6.92820323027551,0.,-2.7));
#457=LINE('',#456,#455);
#458=CARTESIAN_POINT('',(-6.92820323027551,0.,-2.70000000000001));
#459=VERTEX_POINT('',#458);
#460=EDGE_CURVE('E155',#331,#459,#457,.T.);
#461=ORIENTED_EDGE('',*,*,#460,.T.);
#462=DIRECTION('',(0.,0.,1.));
#463=VECTOR('',#462,1.);
#464=CARTESIAN_POINT('',(-6.92820323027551,0.,-22.8000000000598));
#465=LINE('',#464,#463);
#466=CARTESIAN_POINT('',(-6.92820323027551,0.,-20.4666666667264));
#467=VERTEX_POINT('',#466);
#468=EDGE_CURVE('E316',#467,#459,#465,.T.);
#469=ORIENTED_EDGE('',*,*,#468,.F.);
#470=CARTESIAN_POINT('',(-3.46410162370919,-5.99999998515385,-20.4664666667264));
#471=CARTESIAN_POINT('',(-3.46409613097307,-6.00000949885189,-20.5007988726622));
#472=CARTESIAN_POINT('',(-3.46485408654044,-5.99869668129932,-20.5351131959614));
#473=CARTESIAN_POINT('',(-3.46786667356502,-5.99347872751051,-20.6034580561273));
#474=CARTESIAN_POINT('',(-3.47012041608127,-5.98957513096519,-20.6374887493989));
#475=CARTESIAN_POINT('',(-3.47903492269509,-5.97413475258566,-20.7383191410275));
#476=CARTESIAN_POINT('',(-3.4878499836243,-5.95886661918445,-20.8043983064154));
#477=CARTESIAN_POINT('',(-3.51062418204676,-5.91942055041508,-20.9326667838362));
#478=CARTESIAN_POINT('',(-3.52457273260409,-5.89526095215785,-20.9948637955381));
#479=CARTESIAN_POINT('',(-3.55684476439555,-5.83936415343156,-21.1146179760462));
#480=CARTESIAN_POINT('',(-3.57517617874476,-5.80761321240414,-21.1721664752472));
#481=CARTESIAN_POINT('',(-3.62554504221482,-5.72037178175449,-21.3097398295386));
#482=CARTESIAN_POINT('',(-3.65983314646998,-5.66098304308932,-21.3864692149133));
#483=CARTESIAN_POINT('',(-3.73406030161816,-5.53241783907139,-21.5280409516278));
#484=CARTESIAN_POINT('',(-3.77401200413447,-5.46321946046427,-21.5928559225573));
#485=CARTESIAN_POINT('',(-3.88136050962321,-5.27728639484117,-21.7449917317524));
#486=CARTESIAN_POINT('',(-3.95153570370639,-5.1557393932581,-21.8244109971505));
#487=CARTESIAN_POINT('',(-4.0969239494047,-4.90391956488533,-21.9614331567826));
#488=CARTESIAN_POINT('',(-4.1721466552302,-4.77363001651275,-22.0189927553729));
#489=CARTESIAN_POINT('',(-4.32084175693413,-4.51608254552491,-22.1139087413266));
#490=CARTESIAN_POINT('',(-4.39416238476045,-4.38908749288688,-22.1522437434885));
#491=CARTESIAN_POINT('',(-4.54219097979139,-4.13269444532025,-22.2164376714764));
#492=CARTESIAN_POINT('',(-4.61690023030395,-4.00329422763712,-22.2422843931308));
#493=CARTESIAN_POINT('',(-4.76737474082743,-3.74266473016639,-22.2836382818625));
#494=CARTESIAN_POINT('',(-4.84314334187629,-3.61142966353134,-22.2990954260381));
#495=CARTESIAN_POINT('',(-4.99496902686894,-3.34845986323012,-22.3207691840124));
#496=CARTESIAN_POINT('',(-5.07102598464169,-3.2167253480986,-22.3269894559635));
#497=CARTESIAN_POINT('',(-5.23315937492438,-2.93590207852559,-22.3309963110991));
#498=CARTESIAN_POINT('',(-5.3192436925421,-2.7867996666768,-22.3275718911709));
#499=CARTESIAN_POINT('',(-5.49117705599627,-2.48900234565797,-22.309246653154));
#500=CARTESIAN_POINT('',(-5.57702590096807,-2.3403077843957,-22.2943379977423));
#501=CARTESIAN_POINT('',(-5.74735291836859,-2.04529273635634,-22.25154782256));
#502=CARTESIAN_POINT('',(-5.83183641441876,-1.8989630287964,-22.2237535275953));
#503=CARTESIAN_POINT('',(-5.99906894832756,-1.60930778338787,-22.1523915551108));
#504=CARTESIAN_POINT('',(-6.08182056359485,-1.46597778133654,-22.1088493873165));
#505=CARTESIAN_POINT('',(-6.2170629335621,-1.23173112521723,-22.01958472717));
#506=CARTESIAN_POINT('',(-6.27046157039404,-1.13924197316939,-21.9794075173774));
#507=CARTESIAN_POINT('',(-6.37506563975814,-0.958062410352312,-21.8884695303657));
#508=CARTESIAN_POINT('',(-6.42626897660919,-0.869375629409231,-21.8376989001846));
#509=CARTESIAN_POINT('',(-6.52561921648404,-0.697295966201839,-21.7233224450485));
#510=CARTESIAN_POINT('',(-6.5737355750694,-0.613955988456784,-21.6596085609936));
#511=CARTESIAN_POINT('',(-6.6644151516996,-0.45689435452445,-21.5178650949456));
#512=CARTESIAN_POINT('',(-6.7069891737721,-0.383153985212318,-21.4398641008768));
#513=CARTESIAN_POINT('',(-6.77172738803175,-0.271024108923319,-21.2954372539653));
#514=CARTESIAN_POINT('',(-6.79611247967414,-0.22878789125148,-21.2330087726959));
#515=CARTESIAN_POINT('',(-6.83970596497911,-0.153281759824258,-21.1012335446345));
#516=CARTESIAN_POINT('',(-6.85891864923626,-0.120004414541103,-21.0318925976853));
#517=CARTESIAN_POINT('',(-6.88879382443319,-0.0682590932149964,-20.8969339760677));
#518=CARTESIAN_POINT('',(-6.90024702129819,-0.0484215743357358,-20.8320199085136));
#519=CARTESIAN_POINT('',(-6.91752136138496,-0.0185015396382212,-20.6993345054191));
#520=CARTESIAN_POINT('',(-6.92335508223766,-0.00839723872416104,-20.6315699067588));
#521=CARTESIAN_POINT('',(-6.92754146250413,-0.001146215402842,-20.5311268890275));
#522=CARTESIAN_POINT('',(-6.92821688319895,2.36475570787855E-05,-20.4987901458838));
#523=CARTESIAN_POINT('',(-6.92820322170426,-1.48458391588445E-08,-20.4664666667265));
#524=B_SPLINE_CURVE_WITH_KNOTS('',3,(#470,#471,#472,#473,#474,#475,#476,#477,#478,#479,#480,
#481,#482,#483,#484,#485,#486,#487,#488,#489,#490,#491,#492,#493,#494,#495,#496,#497,#498,#499,
#500,#501,#502,#503,#504,#505,#506,#507,#508,#509,#510,#511,#512,#513,#514,#515,#516,#517,#518,
#519,#520,#521,#522,#523),.UNSPECIFIED.,.F.,.F.,(4,2,2,2,2,2,2,2,2,2,2,2,2,2,2,2,2,2,2,2,2,2,2,
2,2,2,4),(0.,0.102928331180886,0.20579554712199,0.409928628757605,0.613643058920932,
0.817729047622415,1.12470488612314,1.43237759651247,1.91344083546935,2.39545196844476,
2.84949009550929,3.30397103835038,3.76062479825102,4.21709765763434,4.73334323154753,
5.24994142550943,5.76309263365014,6.2754162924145,6.61728597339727,6.95947505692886,
7.30464793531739,7.6491375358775,7.88599898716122,8.12266334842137,8.32830181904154,
8.53347894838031,8.63046058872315),.UNSPECIFIED.);
#525=EDGE_CURVE('E204',#339,#467,#524,.T.);
#526=ORIENTED_EDGE('',*,*,#525,.F.);
#527=EDGE_LOOP('',(#453,#461,#469,#526));
#528=FACE_BOUND('',#527,.T.);
#529=ADVANCED_FACE('F318',(#528),#452,.F.);
#530=CARTESIAN_POINT('',(-6.92820323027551,0.,-22.8000000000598));
#531=DIRECTION('',(0.866025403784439,-0.5,0.));
#532=DIRECTION('',(0.5,0.866025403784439,0.));
#533=AXIS2_PLACEMENT_3D('',#530,#531,#532);
#534=PLANE('',#533);
#535=ORIENTED_EDGE('',*,*,#468,.T.);
#536=DIRECTION('',(0.5,0.866025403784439,0.));
#537=VECTOR('',#536,1.);
#538=CARTESIAN_POINT('',(-3.46410161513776,6.,-2.7));
#539=LINE('',#538,#537);
#540=EDGE_CURVE('E157',#459,#31,#539,.T.);
#541=ORIENTED_EDGE('',*,*,#540,.T.);
#542=ORIENTED_EDGE('',*,*,#32,.F.);
#543=CARTESIAN_POINT('',(-6.92820322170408,1.48461529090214E-08,-20.4664666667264));
#544=CARTESIAN_POINT('',(-6.9282087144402,-9.498851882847E-06,-20.5007988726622));
#545=CARTESIAN_POINT('',(-6.92745075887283,0.00130331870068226,-20.5351131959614));
#546=CARTESIAN_POINT('',(-6.92443817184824,0.0065212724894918,-20.6034580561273));
#547=CARTESIAN_POINT('',(-6.922184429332,0.0104248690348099,-20.6374887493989));
#548=CARTESIAN_POINT('',(-6.91326992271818,0.0258652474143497,-20.7383191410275));
#549=CARTESIAN_POINT('',(-6.90445486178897,0.0411333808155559,-20.8043983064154));
#550=CARTESIAN_POINT('',(-6.88168066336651,0.0805794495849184,-20.9326667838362));
#551=CARTESIAN_POINT('',(-6.86773211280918,0.104739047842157,-20.9948637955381));
#552=CARTESIAN_POINT('',(-6.83546008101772,0.160635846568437,-21.1146179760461));
#553=CARTESIAN_POINT('',(-6.81712866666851,0.192386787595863,-21.1721664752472));
#554=CARTESIAN_POINT('',(-6.76675980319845,0.279628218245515,-21.3097398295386));
#555=CARTESIAN_POINT('',(-6.73247169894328,0.339016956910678,-21.3864692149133));
#556=CARTESIAN_POINT('',(-6.65824454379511,0.467582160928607,-21.5280409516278));
#557=CARTESIAN_POINT('',(-6.6182928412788,0.536780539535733,-21.5928559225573));
#558=CARTESIAN_POINT('',(-6.51094433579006,0.722713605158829,-21.7449917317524));
#559=CARTESIAN_POINT('',(-6.44076914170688,0.844260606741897,-21.8244109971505));
#560=CARTESIAN_POINT('',(-6.29538089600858,1.09608043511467,-21.9614331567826));
#561=CARTESIAN_POINT('',(-6.22015819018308,1.22636998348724,-22.0189927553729));
#562=CARTESIAN_POINT('',(-6.07146308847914,1.48391745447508,-22.1139087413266));
#563=CARTESIAN_POINT('',(-5.99814246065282,1.61091250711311,-22.1522437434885));
#564=CARTESIAN_POINT('',(-5.85011386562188,1.86730555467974,-22.2164376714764));
#565=CARTESIAN_POINT('',(-5.77540461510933,1.99670577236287,-22.2422843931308));
#566=CARTESIAN_POINT('',(-5.62493010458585,2.25733526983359,-22.2836382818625));
#567=CARTESIAN_POINT('',(-5.54916150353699,2.38857033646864,-22.2990954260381));
#568=CARTESIAN_POINT('',(-5.39733581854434,2.65154013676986,-22.3207691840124));
#569=CARTESIAN_POINT('',(-5.32127886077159,2.78327465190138,-22.3269894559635));
#570=CARTESIAN_POINT('',(-5.1591454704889,3.06409792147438,-22.3309963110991));
#571=CARTESIAN_POINT('',(-5.07306115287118,3.21320033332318,-22.3275718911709));
#572=CARTESIAN_POINT('',(-4.90112778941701,3.510997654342,-22.309246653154));
#573=CARTESIAN_POINT('',(-4.81527894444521,3.65969221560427,-22.2943379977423));
#574=CARTESIAN_POINT('',(-4.64495192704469,3.95470726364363,-22.25154782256));
#575=CARTESIAN_POINT('',(-4.56046843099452,4.10103697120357,-22.2237535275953));
#576=CARTESIAN_POINT('',(-4.39323589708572,4.3906922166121,-22.1523915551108));
#577=CARTESIAN_POINT('',(-4.31048428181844,4.53402221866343,-22.1088493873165));
#578=CARTESIAN_POINT('',(-4.17524191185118,4.76826887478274,-22.01958472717));
#579=CARTESIAN_POINT('',(-4.12184327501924,4.86075802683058,-21.9794075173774));
#580=CARTESIAN_POINT('',(-4.01723920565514,5.04193758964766,-21.8884695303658));
#581=CARTESIAN_POINT('',(-3.96603586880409,5.13062437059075,-21.8376989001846));
#582=CARTESIAN_POINT('',(-3.86668562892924,5.30270403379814,-21.7233224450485));
#583=CARTESIAN_POINT('',(-3.81856927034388,5.3860440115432,-21.6596085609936));
#584=CARTESIAN_POINT('',(-3.72788969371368,5.54310564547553,-21.5178650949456));
#585=CARTESIAN_POINT('',(-3.68531567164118,5.61684601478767,-21.4398641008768));
#586=CARTESIAN_POINT('',(-3.62057745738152,5.72897589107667,-21.2954372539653));
#587=CARTESIAN_POINT('',(-3.59619236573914,5.7712121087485,-21.2330087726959));
#588=CARTESIAN_POINT('',(-3.55259888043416,5.84671824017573,-21.1012335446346));
#589=CARTESIAN_POINT('',(-3.53338619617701,5.87999558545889,-21.0318925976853));
#590=CARTESIAN_POINT('',(-3.50351102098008,5.93174090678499,-20.8969339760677));
#591=CARTESIAN_POINT('',(-3.49205782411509,5.95157842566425,-20.8320199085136));
#592=CARTESIAN_POINT('',(-3.47478348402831,5.98149846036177,-20.6993345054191));
#593=CARTESIAN_POINT('',(-3.46894976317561,5.99160276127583,-20.6315699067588));
#594=CARTESIAN_POINT('',(-3.46476338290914,5.99885378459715,-20.5311268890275));
#595=CARTESIAN_POINT('',(-3.46408796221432,6.00002364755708,-20.4987901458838));
#596=CARTESIAN_POINT('',(-3.46410162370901,5.99999998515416,-20.4664666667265));
#597=B_SPLINE_CURVE_WITH_KNOTS('',3,(#543,#544,#545,#546,#547,#548,#549,#550,#551,#552,#553,
#554,#555,#556,#557,#558,#559,#560,#561,#562,#563,#564,#565,#566,#567,#568,#569,#570,#571,#572,
#573,#574,#575,#576,#577,#578,#579,#580,#581,#582,#583,#584,#585,#586,#587,#588,#589,#590,#591,
#592,#593,#594,#595,#596),.UNSPECIFIED.,.F.,.F.,(4,2,2,2,2,2,2,2,2,2,2,2,2,2,2,2,2,2,2,2,2,2,2,
2,2,2,4),(0.,0.102928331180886,0.20579554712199,0.409928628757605,0.613643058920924,
0.81772904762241,1.12470488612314,1.43237759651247,1.91344083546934,2.39545196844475,
2.84949009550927,3.30397103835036,3.760624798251,4.21709765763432,4.7333432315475,
5.24994142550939,5.7630926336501,6.27541629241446,6.61728597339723,6.95947505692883,
7.30464793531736,7.64913753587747,7.88599898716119,8.12266334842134,8.32830181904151,
8.53347894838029,8.63046058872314),.UNSPECIFIED.);
#598=EDGE_CURVE('E202',#467,#29,#597,.T.);
#599=ORIENTED_EDGE('',*,*,#598,.F.);
#600=EDGE_LOOP('',(#535,#541,#542,#599));
#601=FACE_BOUND('',#600,.T.);
#602=ADVANCED_FACE('F197',(#601),#534,.F.);
#603=CARTESIAN_POINT('',(-10.3923048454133,5.99999999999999,-22.8000000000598));
#604=DIRECTION('',(0.,0.,1.));
#605=DIRECTION('',(1.,0.,0.));
#606=AXIS2_PLACEMENT_3D('',#603,#604,#605);
#607=PLANE('',#606);
#608=CARTESIAN_POINT('',(0.,0.,-22.8000000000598));
#609=DIRECTION('',(0.,0.,1.));
#610=DIRECTION('',(1.,0.,0.));
#611=AXIS2_PLACEMENT_3D('',#608,#609,#610);
#612=CIRCLE('',#611,3.96666666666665);
#613=CARTESIAN_POINT('',(3.96666666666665,0.,-22.8000000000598));
#614=VERTEX_POINT('',#613);
#615=EDGE_CURVE('E163',#614,#614,#612,.T.);
#616=ORIENTED_EDGE('',*,*,#615,.T.);
#617=EDGE_LOOP('',(#616));
#618=FACE_BOUND('',#617,.T.);
#619=CARTESIAN_POINT('',(0.,0.,-22.8000000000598));
#620=DIRECTION('',(0.,0.,1.));
#621=DIRECTION('',(1.,0.,0.));
#622=AXIS2_PLACEMENT_3D('',#619,#620,#621);
#623=CIRCLE('',#622,4.59486989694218);
#624=CARTESIAN_POINT('',(4.59486989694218,0.,-22.8000000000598));
#625=VERTEX_POINT('',#624);
#626=EDGE_CURVE('E180',#625,#625,#623,.T.);
#627=ORIENTED_EDGE('',*,*,#626,.F.);
#628=EDGE_LOOP('',(#627));
#629=FACE_BOUND('',#628,.T.);
#630=ADVANCED_FACE('F193',(#618,#629),#607,.F.);
#631=CARTESIAN_POINT('',(0.,0.,-1.8));
#632=DIRECTION('',(0.,0.,1.));
#633=DIRECTION('',(1.,0.,0.));
#634=AXIS2_PLACEMENT_3D('',#631,#632,#633);
#635=PLANE('',#634);
#636=DIRECTION('',(-0.5,0.866025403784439,0.));
#637=VECTOR('',#636,1.);
#638=CARTESIAN_POINT('',(-4.24352447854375,-6.45,-1.8));
#639=LINE('',#638,#637);
#640=CARTESIAN_POINT('',(-7.96743371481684,0.,-1.8));
#641=VERTEX_POINT('',#640);
#642=CARTESIAN_POINT('',(-3.98371685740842,-6.9,-1.8));
#643=VERTEX_POINT('',#642);
#644=EDGE_CURVE('E150',#641,#643,#639,.F.);
#645=ORIENTED_EDGE('',*,*,#644,.T.);
#646=DIRECTION('',(-1.,0.,0.));
#647=VECTOR('',#646,1.);
#648=CARTESIAN_POINT('',(3.46410161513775,-6.9,-1.8));
#649=LINE('',#648,#647);
#650=CARTESIAN_POINT('',(3.98371685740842,-6.9,-1.8));
#651=VERTEX_POINT('',#650);
#652=EDGE_CURVE('E152',#643,#651,#649,.F.);
#653=ORIENTED_EDGE('',*,*,#652,.T.);
#654=DIRECTION('',(-0.5,-0.866025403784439,0.));
#655=VECTOR('',#654,1.);
#656=CARTESIAN_POINT('',(7.7076260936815,-0.450000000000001,-1.8));
#657=LINE('',#656,#655);
#658=CARTESIAN_POINT('',(7.96743371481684,0.,-1.8));
#659=VERTEX_POINT('',#658);
#660=EDGE_CURVE('E142',#651,#659,#657,.F.);
#661=ORIENTED_EDGE('',*,*,#660,.T.);
#662=DIRECTION('',(0.5,-0.866025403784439,0.));
#663=VECTOR('',#662,1.);
#664=CARTESIAN_POINT('',(4.24352447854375,6.45,-1.8));
#665=LINE('',#664,#663);
#666=CARTESIAN_POINT('',(3.98371685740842,6.9,-1.8));
#667=VERTEX_POINT('',#666);
#668=EDGE_CURVE('E144',#659,#667,#665,.F.);
#669=ORIENTED_EDGE('',*,*,#668,.T.);
#670=DIRECTION('',(1.,0.,0.));
#671=VECTOR('',#670,1.);
#672=CARTESIAN_POINT('',(-3.46410161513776,6.9,-1.8));
#673=LINE('',#672,#671);
#674=CARTESIAN_POINT('',(-3.98371685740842,6.9,-1.8));
#675=VERTEX_POINT('',#674);
#676=EDGE_CURVE('E146',#667,#675,#673,.F.);
#677=ORIENTED_EDGE('',*,*,#676,.T.);
#678=DIRECTION('',(0.5,0.866025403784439,0.));
#679=VECTOR('',#678,1.);
#680=CARTESIAN_POINT('',(-7.7076260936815,0.450000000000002,-1.8));
#681=LINE('',#680,#679);
#682=EDGE_CURVE('E148',#675,#641,#681,.F.);
#683=ORIENTED_EDGE('',*,*,#682,.T.);
#684=EDGE_LOOP('',(#645,#653,#661,#669,#677,#683));
#685=FACE_BOUND('',#684,.T.);
#686=CARTESIAN_POINT('',(0.,0.,-1.8));
#687=DIRECTION('',(0.,0.,1.));
#688=DIRECTION('',(1.,0.,0.));
#689=AXIS2_PLACEMENT_3D('',#686,#687,#688);
#690=CIRCLE('',#689,9.);
#691=CARTESIAN_POINT('',(9.,0.,-1.8));
#692=VERTEX_POINT('',#691);
#693=EDGE_CURVE('E134',#692,#692,#690,.T.);
#694=ORIENTED_EDGE('',*,*,#693,.F.);
#695=EDGE_LOOP('',(#694));
#696=FACE_BOUND('',#695,.T.);
#697=ADVANCED_FACE('F196',(#685,#696),#635,.F.);
#698=CARTESIAN_POINT('',(0.,0.,-1.8));
#699=DIRECTION('',(0.,0.,1.));
#700=DIRECTION('',(1.,0.,0.));
#701=AXIS2_PLACEMENT_3D('',#698,#699,#700);
#702=CYLINDRICAL_SURFACE('',#701,9.);
#703=ORIENTED_EDGE('',*,*,#693,.T.);
#704=EDGE_LOOP('',(#703));
#705=FACE_BOUND('',#704,.T.);
#706=CARTESIAN_POINT('',(0.,0.,0.));
#707=DIRECTION('',(0.,0.,1.));
#708=DIRECTION('',(1.,0.,0.));
#709=AXIS2_PLACEMENT_3D('',#706,#707,#708);
#710=CIRCLE('',#709,9.);
#711=CARTESIAN_POINT('',(9.,0.,0.));
#712=VERTEX_POINT('',#711);
#713=EDGE_CURVE('E128',#712,#712,#710,.T.);
#714=ORIENTED_EDGE('',*,*,#713,.F.);
#715=EDGE_LOOP('',(#714));
#716=FACE_BOUND('',#715,.T.);
#717=ADVANCED_FACE('F258',(#705,#716),#702,.T.);
#718=CARTESIAN_POINT('',(0.,0.,0.));
#719=DIRECTION('',(0.,0.,1.));
#720=DIRECTION('',(1.,0.,0.));
#721=AXIS2_PLACEMENT_3D('',#718,#719,#720);
#722=PLANE('',#721);
#723=CARTESIAN_POINT('',(0.,0.,-1.70530256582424E-10));
#724=DIRECTION('',(0.,0.,1.));
#725=DIRECTION('',(1.,0.,0.));
#726=AXIS2_PLACEMENT_3D('',#723,#724,#725);
#727=CIRCLE('',#726,5.);
#728=CARTESIAN_POINT('',(5.,0.,-1.70530256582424E-10));
#729=VERTEX_POINT('',#728);
#730=EDGE_CURVE('E324',#729,#729,#727,.T.);
#731=ORIENTED_EDGE('',*,*,#730,.F.);
#732=EDGE_LOOP('',(#731));
#733=FACE_BOUND('',#732,.T.);
#734=ORIENTED_EDGE('',*,*,#713,.T.);
#735=EDGE_LOOP('',(#734));
#736=FACE_BOUND('',#735,.T.);
#737=ADVANCED_FACE('F260',(#733,#736),#722,.T.);
#738=CARTESIAN_POINT('',(0.,0.,-7.30000000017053));
#739=DIRECTION('',(0.,0.,1.));
#740=DIRECTION('',(1.,0.,0.));
#741=AXIS2_PLACEMENT_3D('',#738,#739,#740);
#742=CYLINDRICAL_SURFACE('',#741,5.);
#743=CARTESIAN_POINT('',(0.,0.,-7.30000000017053));
#744=DIRECTION('',(0.,0.,1.));
#745=DIRECTION('',(1.,0.,0.));
#746=AXIS2_PLACEMENT_3D('',#743,#744,#745);
#747=CIRCLE('',#746,5.);
#748=CARTESIAN_POINT('',(5.,0.,-7.30000000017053));
#749=VERTEX_POINT('',#748);
#750=EDGE_CURVE('E321',#749,#749,#747,.T.);
#751=ORIENTED_EDGE('',*,*,#750,.F.);
#752=EDGE_LOOP('',(#751));
#753=FACE_BOUND('',#752,.T.);
#754=ORIENTED_EDGE('',*,*,#730,.T.);
#755=EDGE_LOOP('',(#754));
#756=FACE_BOUND('',#755,.T.);
#757=ADVANCED_FACE('F263',(#753,#756),#742,.F.);
#758=CARTESIAN_POINT('',(0.,0.,-22.8000000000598));
#759=DIRECTION('',(0.,0.,1.));
#760=DIRECTION('',(1.,0.,0.));
#761=AXIS2_PLACEMENT_3D('',#758,#759,#760);
#762=CYLINDRICAL_SURFACE('',#761,3.5);
#763=CARTESIAN_POINT('',(0.,0.,-8.80000000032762));
#764=DIRECTION('',(0.,0.,1.));
#765=DIRECTION('',(1.,0.,0.));
#766=AXIS2_PLACEMENT_3D('',#763,#764,#765);
#767=CIRCLE('',#766,3.5);
#768=CARTESIAN_POINT('',(3.5,0.,-8.80000000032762));
#769=VERTEX_POINT('',#768);
#770=EDGE_CURVE('E11',#769,#769,#767,.T.);
#771=CARTESIAN_POINT('',(0.,0.,-22.3333333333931));
#772=DIRECTION('',(0.,0.,1.));
#773=DIRECTION('',(1.,0.,0.));
#774=AXIS2_PLACEMENT_3D('',#771,#772,#773);
#775=CIRCLE('',#774,3.5);
#776=CARTESIAN_POINT('',(3.5,0.,-22.3333333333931));
#777=VERTEX_POINT('',#776);
#778=EDGE_CURVE('E43',#777,#777,#775,.F.);
#779=CARTESIAN_POINT('',(3.5,0.,-8.80000000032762));
#780=CARTESIAN_POINT('',(3.5,0.,-8.94097222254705));
#781=CARTESIAN_POINT('',(3.5,0.,-9.08194444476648));
#782=CARTESIAN_POINT('',(3.5,0.,-9.36388888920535));
#783=CARTESIAN_POINT('',(3.5,0.,-9.50486111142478));
#784=CARTESIAN_POINT('',(3.5,0.,-9.78680555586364));
#785=CARTESIAN_POINT('',(3.5,0.,-9.92777777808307));
#786=CARTESIAN_POINT('',(3.5,0.,-10.2097222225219));
#787=CARTESIAN_POINT('',(3.5,0.,-10.3506944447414));
#788=CARTESIAN_POINT('',(3.5,0.,-10.6326388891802));
#789=CARTESIAN_POINT('',(3.5,0.,-10.7736111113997));
#790=CARTESIAN_POINT('',(3.5,0.,-11.0555555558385));
#791=CARTESIAN_POINT('',(3.5,0.,-11.196527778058));
#792=CARTESIAN_POINT('',(3.5,0.,-11.4784722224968));
#793=CARTESIAN_POINT('',(3.5,0.,-11.6194444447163));
#794=CARTESIAN_POINT('',(3.5,0.,-11.9013888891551));
#795=CARTESIAN_POINT('',(3.5,0.,-12.0423611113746));
#796=CARTESIAN_POINT('',(3.5,0.,-12.3243055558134));
#797=CARTESIAN_POINT('',(3.5,0.,-12.4652777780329));
#798=CARTESIAN_POINT('',(3.5,0.,-12.7472222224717));
#799=CARTESIAN_POINT('',(3.5,0.,-12.8881944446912));
#800=CARTESIAN_POINT('',(3.5,0.,-13.17013888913));
#801=CARTESIAN_POINT('',(3.5,0.,-13.3111111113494));
#802=CARTESIAN_POINT('',(3.5,0.,-13.5930555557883));
#803=CARTESIAN_POINT('',(3.5,0.,-13.7340277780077));
#804=CARTESIAN_POINT('',(3.5,0.,-14.0159722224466));
#805=CARTESIAN_POINT('',(3.5,0.,-14.156944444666));
#806=CARTESIAN_POINT('',(3.5,0.,-14.4388888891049));
#807=CARTESIAN_POINT('',(3.5,0.,-14.5798611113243));
#808=CARTESIAN_POINT('',(3.5,0.,-14.8618055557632));
#809=CARTESIAN_POINT('',(3.5,0.,-15.0027777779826));
#810=CARTESIAN_POINT('',(3.5,0.,-15.2847222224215));
#811=CARTESIAN_POINT('',(3.5,0.,-15.4256944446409));
#812=CARTESIAN_POINT('',(3.5,0.,-15.7076388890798));
#813=CARTESIAN_POINT('',(3.5,0.,-15.8486111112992));
#814=CARTESIAN_POINT('',(3.5,0.,-16.1305555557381));
#815=CARTESIAN_POINT('',(3.5,0.,-16.2715277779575));
#816=CARTESIAN_POINT('',(3.5,0.,-16.5534722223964));
#817=CARTESIAN_POINT('',(3.5,0.,-16.6944444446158));
#818=CARTESIAN_POINT('',(3.5,0.,-16.9763888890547));
#819=CARTESIAN_POINT('',(3.5,0.,-17.1173611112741));
#820=CARTESIAN_POINT('',(3.5,0.,-17.399305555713));
#821=CARTESIAN_POINT('',(3.5,0.,-17.5402777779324));
#822=CARTESIAN_POINT('',(3.5,0.,-17.8222222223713));
#823=CARTESIAN_POINT('',(3.5,0.,-17.9631944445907));
#824=CARTESIAN_POINT('',(3.5,0.,-18.2451388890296));
#825=CARTESIAN_POINT('',(3.5,0.,-18.386111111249));
#826=CARTESIAN_POINT('',(3.5,0.,-18.6680555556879));
#827=CARTESIAN_POINT('',(3.5,0.,-18.8090277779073));
#828=CARTESIAN_POINT('',(3.5,0.,-19.0909722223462));
#829=CARTESIAN_POINT('',(3.5,0.,-19.2319444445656));
#830=CARTESIAN_POINT('',(3.5,0.,-19.5138888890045));
#831=CARTESIAN_POINT('',(3.5,0.,-19.6548611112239));
#832=CARTESIAN_POINT('',(3.5,0.,-19.9368055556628));
#833=CARTESIAN_POINT('',(3.5,0.,-20.0777777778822));
#834=CARTESIAN_POINT('',(3.5,0.,-20.3597222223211));
#835=CARTESIAN_POINT('',(3.5,0.,-20.5006944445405));
#836=CARTESIAN_POINT('',(3.5,0.,-20.7826388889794));
#837=CARTESIAN_POINT('',(3.5,0.,-20.9236111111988));
#838=CARTESIAN_POINT('',(3.5,0.,-21.2055555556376));
#839=CARTESIAN_POINT('',(3.5,0.,-21.3465277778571));
#840=CARTESIAN_POINT('',(3.5,0.,-21.6284722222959));
#841=CARTESIAN_POINT('',(3.5,0.,-21.7694444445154));
#842=CARTESIAN_POINT('',(3.5,0.,-22.0513888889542));
#843=CARTESIAN_POINT('',(3.5,0.,-22.1923611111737));
#844=CARTESIAN_POINT('',(3.5,0.,-22.3333333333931));
#845=B_SPLINE_CURVE_WITH_KNOTS('',3,(#779,#780,#781,#782,#783,#784,#785,#786,#787,#788,#789,
#790,#791,#792,#793,#794,#795,#796,#797,#798,#799,#800,#801,#802,#803,#804,#805,#806,#807,#808,
#809,#810,#811,#812,#813,#814,#815,#816,#817,#818,#819,#820,#821,#822,#823,#824,#825,#826,#827,
#828,#829,#830,#831,#832,#833,#834,#835,#836,#837,#838,#839,#840,#841,#842,#843,#844),
.UNSPECIFIED.,.F.,.F.,(4,2,2,2,2,2,2,2,2,2,2,2,2,2,2,2,2,2,2,2,2,2,2,2,2,2,2,2,2,2,2,2,4),(0.,
0.422916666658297,0.845833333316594,1.26874999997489,1.69166666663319,2.11458333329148,
2.53749999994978,2.96041666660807,3.38333333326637,3.80624999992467,4.22916666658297,
4.65208333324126,5.07499999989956,5.49791666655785,5.92083333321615,6.34374999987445,
6.76666666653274,7.18958333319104,7.61249999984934,8.03541666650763,8.45833333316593,
8.88124999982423,9.30416666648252,9.72708333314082,10.1499999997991,10.5729166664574,
10.9958333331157,11.418749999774,11.8416666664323,12.2645833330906,12.6874999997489,
13.1104166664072,13.5333333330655),.UNSPECIFIED.);
#846=EDGE_CURVE('BSEAM185',#769,#777,#845,.T.);
#847=ORIENTED_EDGE('',*,*,#770,.T.);
#848=ORIENTED_EDGE('',*,*,#778,.T.);
#849=ORIENTED_EDGE('',*,*,#846,.T.);
#850=ORIENTED_EDGE('',*,*,#846,.F.);
#851=EDGE_LOOP('',(#847,#849,#848,#850));
#852=FACE_BOUND('',#851,.T.);
#853=ADVANCED_FACE('F185',(#852),#762,.F.);
#854=CARTESIAN_POINT('',(0.,0.,-20.4666666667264));
#855=DIRECTION('',(0.,0.,1.));
#856=DIRECTION('',(1.,0.,0.));
#857=AXIS2_PLACEMENT_3D('',#854,#855,#856);
#858=TOROIDAL_SURFACE('',#857,4.59486989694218,2.33333333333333);
#859=ORIENTED_EDGE('',*,*,#626,.T.);
#860=EDGE_LOOP('',(#859));
#861=FACE_BOUND('',#860,.T.);
#862=ORIENTED_EDGE('',*,*,#151,.T.);
#863=ORIENTED_EDGE('',*,*,#233,.T.);
#864=ORIENTED_EDGE('',*,*,#315,.T.);
#865=ORIENTED_EDGE('',*,*,#443,.T.);
#866=ORIENTED_EDGE('',*,*,#525,.T.);
#867=ORIENTED_EDGE('',*,*,#598,.T.);
#868=EDGE_LOOP('',(#862,#863,#864,#865,#866,#867));
#869=FACE_BOUND('',#868,.T.);
#870=ADVANCED_FACE('F110',(#861,#869),#858,.T.);
#871=CARTESIAN_POINT('',(-3.46410161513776,6.9,-2.7));
#872=DIRECTION('',(-1.,0.,0.));
#873=DIRECTION('',(0.,-1.,0.));
#874=AXIS2_PLACEMENT_3D('',#871,#872,#873);
#875=CYLINDRICAL_SURFACE('',#874,0.9);
#876=CARTESIAN_POINT('',(-3.98371685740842,6.9,-2.7));
#877=DIRECTION('',(-0.866025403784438,-0.5,0.));
#878=DIRECTION('',(-0.5,0.866025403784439,0.));
#879=AXIS2_PLACEMENT_3D('',#876,#877,#878);
#880=ELLIPSE('',#879,1.03923048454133,0.9);
#881=EDGE_CURVE('E174',#675,#31,#880,.F.);
#882=ORIENTED_EDGE('',*,*,#881,.F.);
#883=ORIENTED_EDGE('',*,*,#676,.F.);
#884=CARTESIAN_POINT('',(3.98371685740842,6.9,-2.7));
#885=DIRECTION('',(-0.866025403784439,0.5,0.));
#886=DIRECTION('',(0.5,0.866025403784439,0.));
#887=AXIS2_PLACEMENT_3D('',#884,#885,#886);
#888=ELLIPSE('',#887,1.03923048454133,0.9);
#889=EDGE_CURVE('E177',#39,#667,#888,.T.);
#890=ORIENTED_EDGE('',*,*,#889,.F.);
#891=ORIENTED_EDGE('',*,*,#40,.F.);
#892=EDGE_LOOP('',(#882,#883,#890,#891));
#893=FACE_BOUND('',#892,.T.);
#894=ADVANCED_FACE('F223',(#893),#875,.F.);
#895=CARTESIAN_POINT('',(4.24352447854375,6.45,-2.7));
#896=DIRECTION('',(-0.5,0.866025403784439,0.));
#897=DIRECTION('',(-0.866025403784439,-0.5,0.));
#898=AXIS2_PLACEMENT_3D('',#895,#896,#897);
#899=CYLINDRICAL_SURFACE('',#898,0.9);
#900=ORIENTED_EDGE('',*,*,#889,.T.);
#901=ORIENTED_EDGE('',*,*,#668,.F.);
#902=CARTESIAN_POINT('',(7.96743371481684,0.,-2.7));
#903=DIRECTION('',(0.,1.,0.));
#904=DIRECTION('',(1.,0.,0.));
#905=AXIS2_PLACEMENT_3D('',#902,#903,#904);
#906=ELLIPSE('',#905,1.03923048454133,0.9);
#907=EDGE_CURVE('E171',#167,#659,#906,.T.);
#908=ORIENTED_EDGE('',*,*,#907,.F.);
#909=ORIENTED_EDGE('',*,*,#168,.F.);
#910=EDGE_LOOP('',(#900,#901,#908,#909));
#911=FACE_BOUND('',#910,.T.);
#912=ADVANCED_FACE('F282',(#911),#899,.F.);
#913=CARTESIAN_POINT('',(-7.7076260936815,0.450000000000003,-2.7));
#914=DIRECTION('',(-0.5,-0.866025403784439,0.));
#915=DIRECTION('',(0.866025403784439,-0.5,0.));
#916=AXIS2_PLACEMENT_3D('',#913,#914,#915);
#917=CYLINDRICAL_SURFACE('',#916,0.9);
#918=ORIENTED_EDGE('',*,*,#881,.T.);
#919=ORIENTED_EDGE('',*,*,#540,.F.);
#920=CARTESIAN_POINT('',(-7.96743371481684,0.,-2.7));
#921=DIRECTION('',(0.,-1.,0.));
#922=DIRECTION('',(-1.,0.,0.));
#923=AXIS2_PLACEMENT_3D('',#920,#921,#922);
#924=ELLIPSE('',#923,1.03923048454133,0.9);
#925=EDGE_CURVE('E168',#641,#459,#924,.F.);
#926=ORIENTED_EDGE('',*,*,#925,.F.);
#927=ORIENTED_EDGE('',*,*,#682,.F.);
#928=EDGE_LOOP('',(#918,#919,#926,#927));
#929=FACE_BOUND('',#928,.T.);
#930=ADVANCED_FACE('F278',(#929),#917,.F.);
#931=CARTESIAN_POINT('',(7.7076260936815,-0.45,-2.7));
#932=DIRECTION('',(0.5,0.866025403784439,0.));
#933=DIRECTION('',(-0.866025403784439,0.5,0.));
#934=AXIS2_PLACEMENT_3D('',#931,#932,#933);
#935=CYLINDRICAL_SURFACE('',#934,0.9);
#936=ORIENTED_EDGE('',*,*,#907,.T.);
#937=ORIENTED_EDGE('',*,*,#660,.F.);
#938=CARTESIAN_POINT('',(3.98371685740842,-6.9,-2.7));
#939=DIRECTION('',(0.866025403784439,0.5,0.));
#940=DIRECTION('',(-0.5,0.866025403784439,0.));
#941=AXIS2_PLACEMENT_3D('',#938,#939,#940);
#942=ELLIPSE('',#941,1.03923048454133,0.9);
#943=EDGE_CURVE('E166',#249,#651,#942,.T.);
#944=ORIENTED_EDGE('',*,*,#943,.F.);
#945=ORIENTED_EDGE('',*,*,#250,.F.);
#946=EDGE_LOOP('',(#936,#937,#944,#945));
#947=FACE_BOUND('',#946,.T.);
#948=ADVANCED_FACE('F274',(#947),#935,.F.);
#949=CARTESIAN_POINT('',(-4.24352447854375,-6.45,-2.7));
#950=DIRECTION('',(0.5,-0.866025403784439,0.));
#951=DIRECTION('',(0.866025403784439,0.5,0.));
#952=AXIS2_PLACEMENT_3D('',#949,#950,#951);
#953=CYLINDRICAL_SURFACE('',#952,0.9);
#954=ORIENTED_EDGE('',*,*,#925,.T.);
#955=ORIENTED_EDGE('',*,*,#460,.F.);
#956=CARTESIAN_POINT('',(-3.98371685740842,-6.9,-2.7));
#957=DIRECTION('',(0.866025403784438,-0.5,0.));
#958=DIRECTION('',(-0.5,-0.866025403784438,0.));
#959=AXIS2_PLACEMENT_3D('',#956,#957,#958);
#960=ELLIPSE('',#959,1.03923048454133,0.9);
#961=EDGE_CURVE('E164',#643,#331,#960,.F.);
#962=ORIENTED_EDGE('',*,*,#961,.F.);
#963=ORIENTED_EDGE('',*,*,#644,.F.);
#964=EDGE_LOOP('',(#954,#955,#962,#963));
#965=FACE_BOUND('',#964,.T.);
#966=ADVANCED_FACE('F270',(#965),#953,.F.);
#967=CARTESIAN_POINT('',(3.46410161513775,-6.9,-2.7));
#968=DIRECTION('',(1.,0.,0.));
#969=DIRECTION('',(0.,1.,0.));
#970=AXIS2_PLACEMENT_3D('',#967,#968,#969);
#971=CYLINDRICAL_SURFACE('',#970,0.9);
#972=ORIENTED_EDGE('',*,*,#943,.T.);
#973=ORIENTED_EDGE('',*,*,#652,.F.);
#974=ORIENTED_EDGE('',*,*,#961,.T.);
#975=ORIENTED_EDGE('',*,*,#332,.F.);
#976=EDGE_LOOP('',(#972,#973,#974,#975));
#977=FACE_BOUND('',#976,.T.);
#978=ADVANCED_FACE('F190',(#977),#971,.F.);
#979=CARTESIAN_POINT('',(0.,0.,-22.8000000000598));
#980=DIRECTION('',(0.,0.,-1.));
#981=DIRECTION('',(-1.,0.,0.));
#982=AXIS2_PLACEMENT_3D('',#979,#980,#981);
#983=CONICAL_SURFACE('',#982,3.96666666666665,0.785398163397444);
#984=ORIENTED_EDGE('',*,*,#778,.F.);
#985=EDGE_LOOP('',(#984));
#986=FACE_BOUND('',#985,.T.);
#987=ORIENTED_EDGE('',*,*,#615,.F.);
#988=EDGE_LOOP('',(#987));
#989=FACE_BOUND('',#988,.T.);
#990=ADVANCED_FACE('F187',(#986,#989),#983,.F.);
#991=CARTESIAN_POINT('',(0.,0.,-8.80000000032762));
#992=DIRECTION('',(0.,0.,1.));
#993=DIRECTION('',(1.,0.,0.));
#994=AXIS2_PLACEMENT_3D('',#991,#992,#993);
#995=CONICAL_SURFACE('',#994,3.5,0.785398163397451);
#996=ORIENTED_EDGE('',*,*,#750,.T.);
#997=EDGE_LOOP('',(#996));
#998=FACE_BOUND('',#997,.T.);
#999=ORIENTED_EDGE('',*,*,#770,.F.);
#1000=EDGE_LOOP('',(#999));
#1001=FACE_BOUND('',#1000,.T.);
#1002=ADVANCED_FACE('F37',(#998,#1001),#995,.F.);
#1003=CLOSED_SHELL('',(#155,#237,#319,#447,#529,#602,#630,#697,#717,#737,#757,#853,#870,#894,
#912,#930,#948,#966,#978,#990,#1002));
#1004=MANIFOLD_SOLID_BREP('B2',#1003);
#1005=ADVANCED_BREP_SHAPE_REPRESENTATION('',(#18,#1004),#14);
#1006=SHAPE_DEFINITION_REPRESENTATION(#9,#1005);
ENDSEC;
END-ISO-10303-21;
